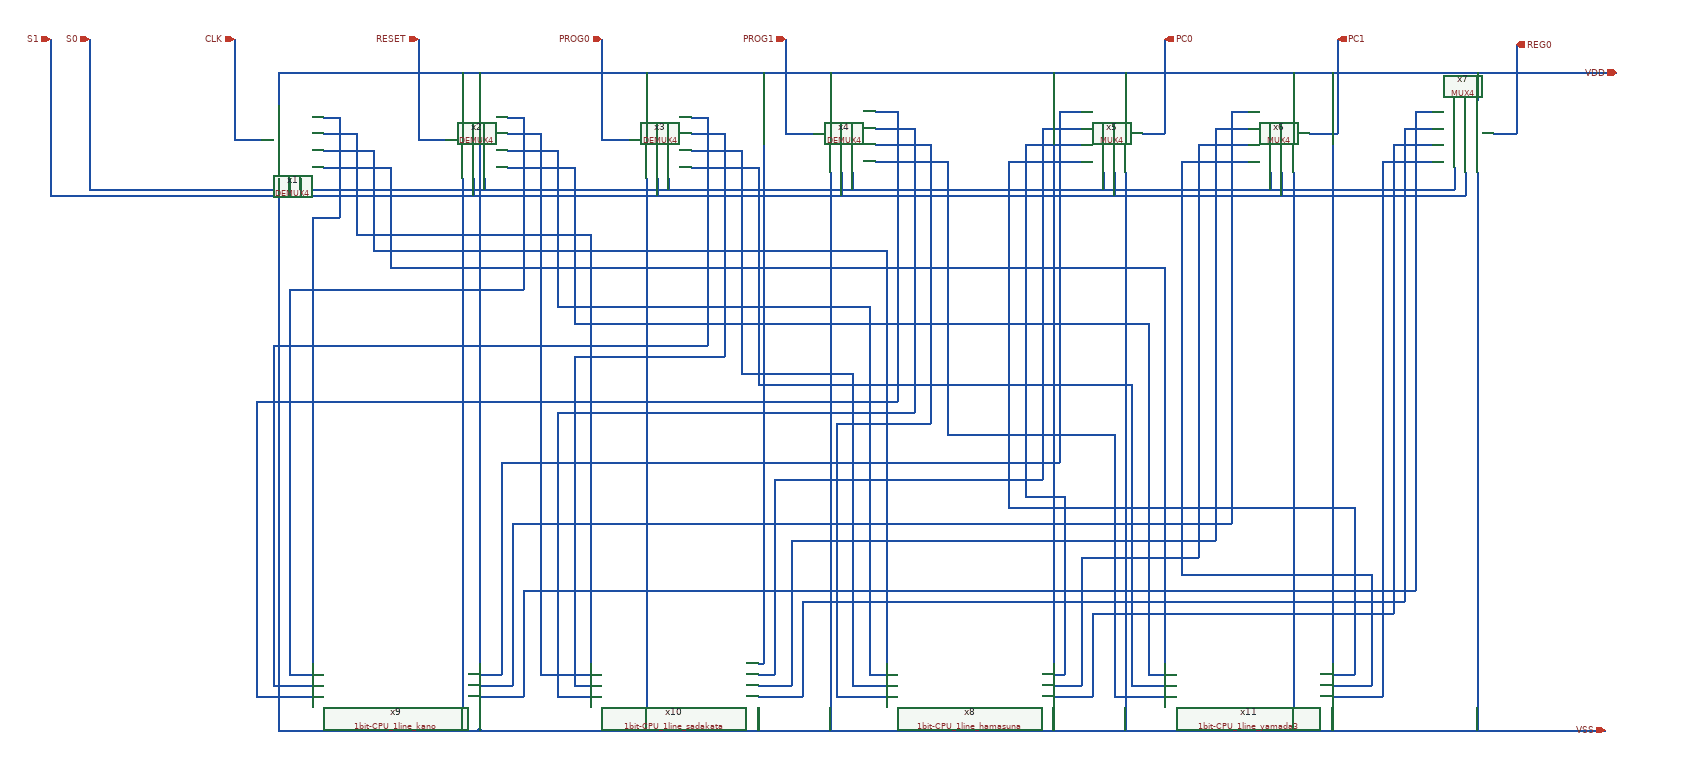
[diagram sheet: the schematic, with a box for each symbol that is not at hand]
v {xschem version=3.4.8RC file_version=1.3}
G {}
K {}
V {}
S {}
F {}
E {}
N -890 -170 -860 -170 {lab=#net1}
N -860 -170 -860 10 {lab=#net1}
N -910 10 -860 10 {lab=#net1}
N -890 -140 -830 -140 {lab=#net2}
N -830 -140 -830 40 {lab=#net2}
N -830 40 -410 40 {lab=#net2}
N -890 -110 -800 -110 {lab=#net3}
N -800 -110 -800 70 {lab=#net3}
N -800 70 120 70 {lab=#net3}
N -890 -80 -770 -80 {lab=#net4}
N -770 -80 -770 100 {lab=#net4}
N -770 100 590 100 {lab=#net4}
N -560 -170 -530 -170 {lab=#net5}
N -530 -170 -530 140 {lab=#net5}
N -950 140 -530 140 {lab=#net5}
N -950 830 -910 830 {lab=#net5}
N -560 -140 -500 -140 {lab=#net6}
N -500 -140 -500 170 {lab=#net6}
N -500 830 -410 830 {lab=#net6}
N -560 -110 -470 -110 {lab=#net7}
N -470 -110 -470 170 {lab=#net7}
N -470 170 90 170 {lab=#net7}
N 90 830 120 830 {lab=#net7}
N -560 -80 -440 -80 {lab=#net8}
N -440 -80 -440 200 {lab=#net8}
N -440 200 560 200 {lab=#net8}
N 590 830 620 830 {lab=#net8}
N -230 -170 -200 -170 {lab=#net9}
N -200 -170 -200 240 {lab=#net9}
N -980 240 -200 240 {lab=#net9}
N -980 850 -910 850 {lab=#net9}
N -230 -140 -170 -140 {lab=#net10}
N -170 -140 -170 260 {lab=#net10}
N -440 260 -170 260 {lab=#net10}
N -440 850 -410 850 {lab=#net10}
N -230 -110 -140 -110 {lab=#net11}
N -140 -110 -140 290 {lab=#net11}
N -140 290 60 290 {lab=#net11}
N 60 850 120 850 {lab=#net11}
N -230 -80 -110 -80 {lab=#net12}
N -110 -80 -110 310 {lab=#net12}
N -110 310 530 310 {lab=#net12}
N 560 850 620 850 {lab=#net12}
N 100 -180 140 -180 {lab=#net13}
N 140 -180 140 340 {lab=#net13}
N -1010 340 140 340 {lab=#net13}
N -1010 870 -910 870 {lab=#net13}
N 100 -150 170 -150 {lab=#net14}
N 170 -150 170 360 {lab=#net14}
N -470 360 170 360 {lab=#net14}
N -470 870 -410 870 {lab=#net14}
N 100 -120 200 -120 {lab=#net15}
N 200 -120 200 380 {lab=#net15}
N 30 380 200 380 {lab=#net15}
N 30 870 120 870 {lab=#net15}
N 100 -90 230 -90 {lab=#net16}
N 230 -90 230 400 {lab=#net16}
N 230 400 500 400 {lab=#net16}
N 530 870 620 870 {lab=#net16}
N 430 -180 470 -180 {lab=#net17}
N 430 -180 430 450 {lab=#net17}
N -570 450 430 450 {lab=#net17}
N -610 830 -570 830 {lab=#net17}
N 400 -150 470 -150 {lab=#net18}
N 400 -150 400 480 {lab=#net18}
N -80 480 400 480 {lab=#net18}
N -110 830 -80 830 {lab=#net18}
N 370 -120 470 -120 {lab=#net19}
N 370 -120 370 510 {lab=#net19}
N 370 510 440 510 {lab=#net19}
N 420 830 440 830 {lab=#net19}
N 340 -90 470 -90 {lab=#net20}
N 340 -90 340 530 {lab=#net20}
N 340 530 960 530 {lab=#net20}
N 920 830 960 830 {lab=#net20}
N 740 -180 770 -180 {lab=#net21}
N 740 -180 740 560 {lab=#net21}
N -550 560 740 560 {lab=#net21}
N -610 850 -550 850 {lab=#net21}
N 710 -150 770 -150 {lab=#net22}
N 710 -150 710 590 {lab=#net22}
N -50 590 710 590 {lab=#net22}
N -50 590 -50 850 {lab=#net22}
N -110 850 -50 850 {lab=#net22}
N 680 -120 770 -120 {lab=#net23}
N 680 -120 680 620 {lab=#net23}
N 470 620 680 620 {lab=#net23}
N 470 620 470 850 {lab=#net23}
N 420 850 470 850 {lab=#net23}
N 650 -90 770 -90 {lab=#net24}
N 650 -90 650 650 {lab=#net24}
N 650 650 990 650 {lab=#net24}
N 920 850 990 850 {lab=#net24}
N 990 650 990 850 {lab=#net24}
N 1070 -180 1100 -180 {lab=#net25}
N 1070 -180 1070 680 {lab=#net25}
N -530 680 -530 870 {lab=#net25}
N -610 870 -530 870 {lab=#net25}
N -530 680 1070 680 {lab=#net25}
N 1050 -150 1100 -150 {lab=#net26}
N 1050 -150 1050 700 {lab=#net26}
N -30 700 1050 700 {lab=#net26}
N -30 700 -30 870 {lab=#net26}
N -110 870 -30 870 {lab=#net26}
N 1030 -120 1100 -120 {lab=#net27}
N 490 720 490 870 {lab=#net27}
N 420 870 490 870 {lab=#net27}
N 1030 -120 1030 720 {lab=#net27}
N 490 720 1030 720 {lab=#net27}
N 1010 -90 1100 -90 {lab=#net28}
N 1010 -90 1010 870 {lab=#net28}
N 920 870 1010 870 {lab=#net28}
N 960 530 960 830 {lab=#net20}
N -910 10 -910 810 {lab=#net1}
N 620 100 620 810 {lab=#net4}
N 590 100 620 100 {lab=#net4}
N -950 140 -950 830 {lab=#net5}
N -980 240 -980 850 {lab=#net9}
N -1010 340 -1010 870 {lab=#net13}
N -410 40 -410 810 {lab=#net2}
N -500 170 -500 830 {lab=#net6}
N -570 450 -570 830 {lab=#net17}
N -550 560 -550 850 {lab=#net21}
N -440 260 -440 850 {lab=#net10}
N -470 360 -470 870 {lab=#net14}
N -80 480 -80 830 {lab=#net18}
N 30 380 30 870 {lab=#net15}
N 60 290 60 850 {lab=#net11}
N 90 170 90 830 {lab=#net7}
N 120 70 120 810 {lab=#net3}
N 590 200 590 830 {lab=#net8}
N 560 200 590 200 {lab=#net8}
N 530 310 560 310 {lab=#net12}
N 560 310 560 850 {lab=#net12}
N 500 400 530 400 {lab=#net16}
N 530 400 530 870 {lab=#net16}
N 1210 -140 1250 -140 {lab=REG0}
N 1250 -300 1250 -140 {lab=REG0}
N 880 -140 930 -140 {lab=PC1}
N 930 -310 930 -140 {lab=PC1}
N 580 -140 620 -140 {lab=PC0}
N 620 -310 620 -140 {lab=PC0}
N -60 -140 -10 -140 {lab=PROG1}
N -60 -310 -60 -140 {lab=PROG1}
N -390 -130 -340 -130 {lab=PROG0}
N -390 -310 -390 -130 {lab=PROG0}
N -720 -130 -670 -130 {lab=RESET}
N -720 -310 -720 -130 {lab=RESET}
N -1050 -130 -1000 -130 {lab=CLK}
N -1050 -310 -1050 -130 {lab=CLK}
N -1310 -310 -1310 -40 {lab=S0}
N -1310 -40 1140 -40 {lab=S0}
N 1140 -80 1140 -40 {lab=S0}
N 1160 -70 1160 -30 {lab=S1}
N -1380 -30 1160 -30 {lab=S1}
N -1380 -310 -1380 -30 {lab=S1}
N -930 -60 -930 -40 {lab=S0}
N -950 -60 -950 -30 {lab=S1}
N -620 -60 -620 -30 {lab=S1}
N -600 -60 -600 -40 {lab=S0}
N -290 -60 -290 -30 {lab=S1}
N -270 -60 -270 -40 {lab=S0}
N 40 -70 40 -30 {lab=S1}
N 60 -70 60 -40 {lab=S0}
N 530 -70 530 -30 {lab=S1}
N 510 -70 510 -40 {lab=S0}
N 810 -70 810 -40 {lab=S0}
N 830 -70 830 -30 {lab=S1}
N -970 -250 1430 -250 {lab=VDD}
N -970 -250 -970 -190 {lab=VDD}
N -640 -250 -640 -190 {lab=VDD}
N -310 -250 -310 -190 {lab=VDD}
N 20 -250 20 -200 {lab=VDD}
N 550 -250 550 -200 {lab=VDD}
N 850 -250 850 -200 {lab=VDD}
N 1180 -250 1180 -200 {lab=VDD}
N -610 -250 -610 810 {lab=VDD}
N -110 810 -100 810 {lab=VDD}
N -100 -250 -100 810 {lab=VDD}
N 440 510 440 830 {lab=#net19}
N 420 -250 420 810 {lab=VDD}
N 920 -250 920 810 {lab=VDD}
N -610 930 1410 930 {lab=VSS}
N -610 890 -610 930 {lab=VSS}
N -110 890 -110 930 {lab=VSS}
N 420 890 420 930 {lab=VSS}
N 920 890 920 930 {lab=VSS}
N 1180 -70 1180 930 {lab=VSS}
N 850 -70 850 930 {lab=VSS}
N 550 -70 550 930 {lab=VSS}
N 20 -70 20 930 {lab=VSS}
N -310 -60 -310 930 {lab=VSS}
N -970 -60 -970 930 {lab=VSS}
N -970 930 -610 930 {lab=VSS}
N -640 -60 -640 930 {lab=VSS}
C {DEMUX4.sym} -980 -120 0 0 {name=x1}
C {DEMUX4.sym} -650 -120 0 0 {name=x2}
C {DEMUX4.sym} -320 -120 0 0 {name=x3}
C {DEMUX4.sym} 10 -130 0 0 {name=x4}
C {MUX4.sym} 490 -130 0 0 {name=x5}
C {MUX4.sym} 790 -130 0 0 {name=x6}
C {MUX4.sym} 1120 -130 0 0 {name=x7}
C {devices/ipin.sym} -1050 -310 0 0 {name=p4 lab=CLK}
C {devices/ipin.sym} -720 -310 0 0 {name=p1 lab=RESET}
C {devices/ipin.sym} -390 -310 0 0 {name=p2 lab=PROG0}
C {devices/ipin.sym} -60 -310 0 0 {name=p3 lab=PROG1}
C {devices/opin.sym} 620 -310 0 0 {name=p7 lab=PC0}
C {devices/opin.sym} 930 -310 0 0 {name=p5 lab=PC1}
C {devices/opin.sym} 1250 -300 0 0 {name=p6 lab=REG0}
C {devices/iopin.sym} 1430 -250 0 0 {name=p8 lab=VDD}
C {devices/iopin.sym} 1410 930 0 0 {name=p9 lab=VSS}
C {devices/ipin.sym} -1310 -310 0 0 {name=p10 lab=S0}
C {devices/ipin.sym} -1380 -310 0 0 {name=p11 lab=S1}
C {1bit-CPU_1line_hamasuna.sym} 270 850 0 0 {name=x8}
C {1bit-CPU_1line_kano.sym} -760 850 0 0 {name=x9}
C {1bit-CPU_1line_sadakata.sym} -260 850 0 0 {name=x10}
C {1bit-CPU_1line_yamada3.sym} 770 850 0 0 {name=x11}
